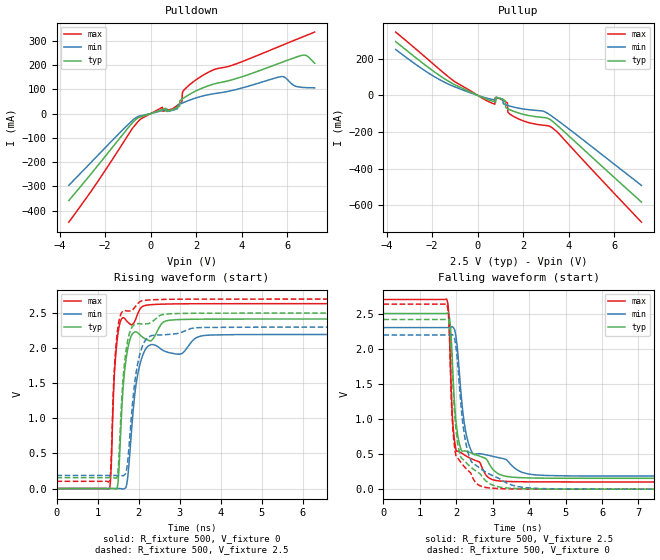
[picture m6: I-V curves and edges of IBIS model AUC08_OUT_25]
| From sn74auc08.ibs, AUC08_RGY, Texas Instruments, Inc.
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[Model]   AUC08_OUT_25
Model_type  Output
Vref =   0
Rref =   500
Cref =   30p
Vmeas =   1.25
| variable   typ   min   max
C_comp   7.45pF   0.27pF   23.62pF
| C_pullup   8.36pF   0.27pF   23.62pF
| C_pulldown   6.53pF   1.89pF   15.75pF
[Temperature Range]   40   100   -40
| Ambient temperature   25   85   -40
[Voltage range]   2.5   2.3   2.7
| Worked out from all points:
|   slope of the pulldown table from 0 to 0.375 V, typ, clamps not added: 30.9 ohm
|   slope of the pullup table from 0 to 0.375 V, typ, clamps not added: 19.2 ohm
|   rising waveform, R_fixture 500, V_fixture 0: 20-80 % time 179ps typ, 248ps min, 131ps max; typ from 0 V to 2.42 V
|   falling waveform, R_fixture 500, V_fixture 2.5: 20-80 % time 223ps typ, 311ps min, 152ps max; typ from 2.5 V to 0.154 V
|   rising waveform, R_fixture 500, V_fixture 2.5: 20-80 % time 177ps typ, 247ps min, 129ps max; typ from 0.154 V to 2.5 V
|   falling waveform, R_fixture 500, V_fixture 0: 20-80 % time 237ps typ, 332ps min, 156ps max; typ from 2.42 V to 0 V
[Pulldown]
| AUC08_OUT_25
|   Voltage   I(typ)   I(min)   I(max)
-3.6V     -357.9mA   -295mA     -446.9mA
-445mV    -13.39mA   -9.086mA   -23.04mA
515mV     17.02mA    12.57mA    25.99mA
1.03V     19.04mA    15.49mA    23.85mA
1.27V     29.99mA    38.36mA    41.3mA
1.37V     59.29mA    42.41mA    48.87mA
1.395V    60.81mA    43.42mA    85.06mA
1.48V     65.92mA    46.77mA    98.72mA
2.545V    114.8mA    77.91mA    170.6mA
5.695V    208.4mA    151.5mA    277.8mA
6.74V     240.4mA    107.1mA    317.8mA
7.2V      207mA      105.9mA    335.2mA
[Pullup]
| AUC08_OUT_25
|   Voltage   I(typ)   I(min)   I(max)
-3.6V     293.6mA    250.5mA    345.5mA
-960mV    55.5mA     44.14mA    71.53mA
730mV     -33.82mA   -24.42mA   -47.21mA
760mV     -34.84mA   -25.13mA   -47.16mA
770mV     -35.18mA   -25.36mA   -13.07mA
1.115V    -23.84mA   -20.26mA   -27.67mA
1.215V    -28.81mA   -50.48mA   -34.67mA
1.295V    -71.05mA   -53.78mA   -40.2mA
1.345V    -74.3mA    -55.73mA   -93.3mA
1.755V    -94.43mA   -68.81mA   -126mA
3.31V     -143.6mA   -118mA     -180.4mA
7.2V      -582.7mA   -491.8mA   -692.5mA
[Ramp]
| AUC08_OUT_25
| variable   typ   min   max
dV/dt_r   1.45/1.80E-10   1.32/2.49E-10   1.59/1.31E-10
dV/dt_f   1.41/2.24E-10   1.28/3.12E-10   1.56/1.54E-10
R_load = 500
[Rising Waveform]
| AUC08_OUT_25
R_fixture =   500
C_fixture =   0
L_fixture =   0
V_fixture =   0
V_fixture_min = 0
V_fixture_max = 0
|   Time   V(typ)   V(min)   V(max)
0s        9.791nV    28.67nV    1.858nV
1.29ns    167.6uV    -2.987uV   3.738mV
1.33ns    302.2uV    -4.433uV   270.1mV
1.415ns   -2.952mV   59.06uV    1.67V
1.525ns   312.5mV    671.3uV    2.307V
1.625ns   1.452V     -6.602mV   2.435V
1.745ns   2.018V     210mV      2.368V
1.935ns   2.232V     1.466V     2.422V
2.16ns    2.133V     1.976V     2.609V
20ns      2.416V     2.195V     2.634V
[Falling Waveform]
| AUC08_OUT_25
R_fixture =   500
C_fixture =   0
L_fixture =   0
V_fixture =   2.5
V_fixture_min = 2.3
V_fixture_max = 2.7
|   Time   V(typ)   V(min)   V(max)
0s        2.5V       2.3V       2.7V
1.74ns    2.503V     2.3V       2.703V
1.79ns    2.5V       2.3V       2.519V
1.835ns   2.34V      2.303V     1.887V
1.9ns     1.735V     2.31V      988.4mV
1.995ns   950.7mV    2.158V     555mV
2.19ns    542.8mV    1.055V     498.2mV
2.35ns    526.9mV    627.2mV    449.4mV
3.035ns   265mV      463.1mV    128.6mV
20ns      154.5mV    186.3mV    102.7mV
[Rising Waveform]
| AUC08_OUT_25
R_fixture =   500
C_fixture =   0
L_fixture =   0
V_fixture =   2.5
V_fixture_min = 2.3
V_fixture_max = 2.7
|   Time   V(typ)   V(min)   V(max)
0s        154.5mV    186.3mV    102.6mV
1.29ns    154.6mV    186.2mV    107.2mV
1.41ns    152.7mV    186.3mV    1.711V
1.515ns   392.1mV    186.8mV    2.365V
1.615ns   1.506V     181.5mV    2.527V
1.72ns    2.057V     309.4mV    2.53V
1.905ns   2.34V      1.502V     2.58V
2.08ns    2.346V     2.008V     2.675V
3.56ns    2.498V     2.295V     2.7V
20ns      2.5V       2.3V       2.7V
[Falling Waveform]
| AUC08_OUT_25
R_fixture =   500
C_fixture =   0
L_fixture =   0
V_fixture =   0
V_fixture_min = 0
V_fixture_max = 0
|   Time   V(typ)   V(min)   V(max)
0s        2.416V     2.195V     2.634V
1.74ns    2.416V     2.195V     2.635V
1.79ns    2.407V     2.195V     2.439V
1.83ns    2.261V     2.196V     1.869V
1.89ns    1.711V     2.201V     992.4mV
1.985ns   887.7mV    2.049V     489.6mV
2.29ns    367.3mV    589.7mV    282.3mV
2.755ns   148.8mV    261.5mV    30.32mV
4.4ns     1.984mV    7.727mV    589.5uV
20ns      23.87uV    3.666uV    11.61uV
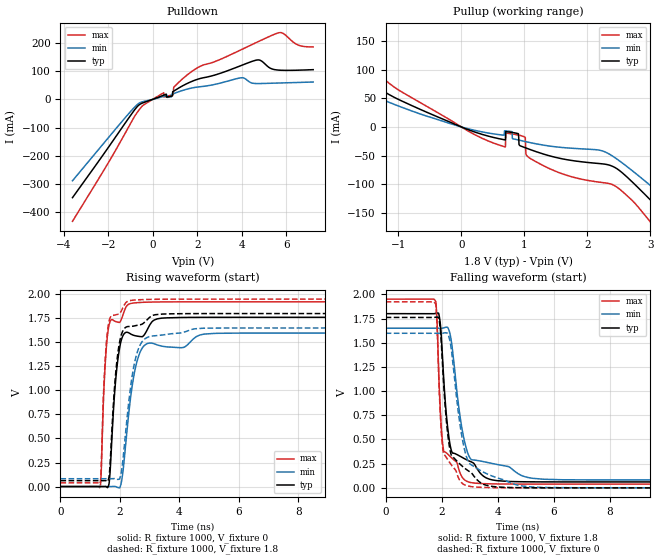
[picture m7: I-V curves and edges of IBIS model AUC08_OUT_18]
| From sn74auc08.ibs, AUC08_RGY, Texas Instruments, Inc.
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[Model]   AUC08_OUT_18
Model_type  Output
Vref =   0
Rref =   1000
Cref =   30p
Vmeas =   0.9
| variable   typ   min   max
C_comp   6.69pF   0.25pF   21.38pF
| C_pullup   7.14pF   1.04pF   21.38pF
| C_pulldown   6.24pF   0.25pF   15.43pF
[Temperature Range]   40   100   -40
| Ambient temperature   25   85   -40
[Voltage range]   1.8   1.65   1.95
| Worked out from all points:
|   slope of the pulldown table from 0 to 0.27 V, typ, clamps not added: 34.4 ohm
|   slope of the pullup table from 0 to 0.27 V, typ, clamps not added: 24.7 ohm
|   rising waveform, R_fixture 1000, V_fixture 0: 20-80 % time 267ps typ, 398ps min, 176ps max; typ from 0 V to 1.76 V
|   falling waveform, R_fixture 1000, V_fixture 1.8: 20-80 % time 316ps typ, 471ps min, 196ps max; typ from 1.8 V to 0.061 V
|   rising waveform, R_fixture 1000, V_fixture 1.8: 20-80 % time 261ps typ, 389ps min, 173ps max; typ from 0.061 V to 1.8 V
|   falling waveform, R_fixture 1000, V_fixture 0: 20-80 % time 325ps typ, 483ps min, 196ps max; typ from 1.76 V to 0 V
[Pulldown]
| AUC08_OUT_18
|   Voltage   I(typ)   I(min)   I(max)
-3.6V     -347.6mA   -287.8mA   -431.2mA
-830mV    -38.94mA   -28.94mA   -62.22mA
-405mV    -11.33mA   -7.446mA   -19.55mA
495mV     14.95mA    10.62mA    23.51mA
885mV     12.26mA    19.06mA    15.87mA
925mV     28.54mA    20.16mA    16.88mA
960mV     30.1mA     21.15mA    44.31mA
2.045V    71.87mA    43.99mA    113.3mA
3.92V     118.2mA    75.85mA    173.7mA
4.625V    138.4mA    55.98mA    200.1mA
5.58V     103.9mA    57.6mA     233.8mA
7.2V      105mA      61.31mA    185.3mA
[Pullup]
| AUC08_OUT_18
|   Voltage   I(typ)   I(min)   I(max)
-3.6V     267.6mA    221.5mA    318.7mA
-2.61V    174.3mA    138.3mA    219.8mA
-2.13V    131.5mA    101.8mA    171.7mA
110mV     -4.812mA   -3.244mA   -7.318mA
695mV     -22.64mA   -6.826mA   -34.84mA
705mV     -8.168mA   -6.941mA   -10.57mA
980mV     -34.9mA    -24.66mA   -16.5mA
1.11V     -40.21mA   -27.81mA   -56.13mA
2.25V     -64.62mA   -42.31mA   -97.29mA
3.1V      -138.6mA   -111.4mA   -179.7mA
3.915V    -230.4mA   -188mA     -289.7mA
7.2V      -598mA     -503.3mA   -721.1mA
[Ramp]
| AUC08_OUT_18
| variable   typ   min   max
dV/dt_r   1.06/2.67E-10   0.97/4.00E-10   1.16/1.76E-10
dV/dt_f   1.05/3.17E-10   0.95/4.75E-10   1.15/1.97E-10
R_load = 1000
[Rising Waveform]
| AUC08_OUT_18
R_fixture =   1000
C_fixture =   0
L_fixture =   0
V_fixture =   0
V_fixture_min = 0
V_fixture_max = 0
|   Time   V(typ)   V(min)   V(max)
0s        7.669nV    26.14nV    1.117nV
1.33ns    -4.227uV   -2.974uV   -4.822mV
1.485ns   449.1uV    -11.66uV   1.155V
1.605ns   -1.293mV   -5.677uV   1.627V
1.955ns   1.374V     -11.6mV    1.708V
2.09ns    1.561V     123.7mV    1.774V
2.345ns   1.591V     885.8mV    1.903V
2.83ns    1.582V     1.47V      1.917V
4.835ns   1.761V     1.587V     1.922V
20ns      1.761V     1.597V     1.922V
[Falling Waveform]
| AUC08_OUT_18
R_fixture =   1000
C_fixture =   0
L_fixture =   0
V_fixture =   1.8
V_fixture_min = 1.65
V_fixture_max = 1.95
|   Time   V(typ)   V(min)   V(max)
0s        1.8V       1.65V      1.95V
1.79ns    1.803V     1.65V      1.926V
1.94ns    1.72V      1.649V     861.6mV
2.065ns   1.161V     1.653V     389.6mV
2.195ns   670.9mV    1.66V      353.9mV
2.345ns   385.9mV    1.512V     312.6mV
2.675ns   323.6mV    699.3mV    140.1mV
2.96ns    280.2mV    336.5mV    60.91mV
5.635ns   61.7mV     89.17mV    38.82mV
20ns      61.08mV    81.21mV    38.69mV
[Rising Waveform]
| AUC08_OUT_18
R_fixture =   1000
C_fixture =   0
L_fixture =   0
V_fixture =   1.8
V_fixture_min = 1.65
V_fixture_max = 1.95
|   Time   V(typ)   V(min)   V(max)
0s        61.05mV    81.2mV     38.68mV
1.33ns    61.04mV    81.2mV     35.1mV
1.485ns   61.49mV    81.19mV    1.2V
1.6ns     60mV       81.2mV     1.658V
1.94ns    1.406V     74.56mV    1.792V
2.07ns    1.598V     194.1mV    1.84V
2.305ns   1.665V     896mV      1.932V
2.785ns   1.697V     1.521V     1.945V
4.515ns   1.799V     1.641V     1.95V
20ns      1.8V       1.65V      1.95V
[Falling Waveform]
| AUC08_OUT_18
R_fixture =   1000
C_fixture =   0
L_fixture =   0
V_fixture =   0
V_fixture_min = 0
V_fixture_max = 0
|   Time   V(typ)   V(min)   V(max)
0s        1.761V     1.597V     1.922V
1.79ns    1.764V     1.597V     1.895V
1.93ns    1.69V      1.597V     884mV
2.055ns   1.141V     1.599V     370.3mV
2.185ns   637.9mV    1.601V     305.2mV
2.32ns    360.9mV    1.477V     247.2mV
2.635ns   250.2mV    688.9mV    82.21mV
2.875ns   191.1mV    329.2mV    24.05mV
5.195ns   996.1uV    9.726mV    211.6uV
20ns      28.23uV    5.954uV    12.23uV
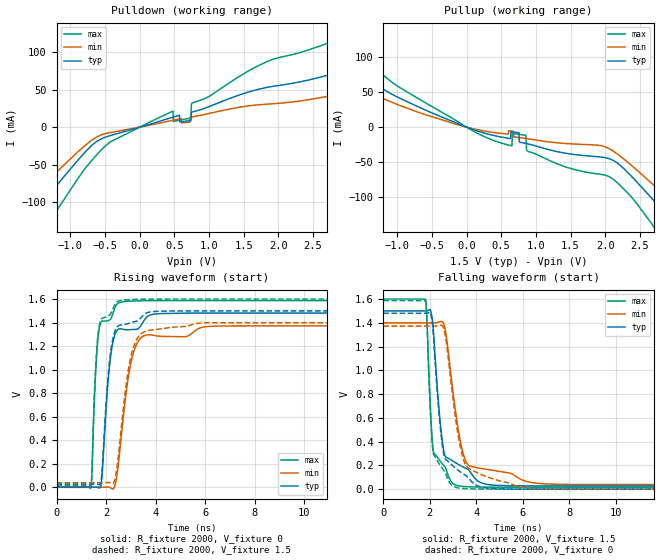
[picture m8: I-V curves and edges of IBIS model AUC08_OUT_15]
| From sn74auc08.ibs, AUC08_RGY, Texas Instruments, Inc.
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[Model]   AUC08_OUT_15
Model_type  Output
Vref =   0
Rref =   2000
Cref =   15p
Vmeas =   0.75
| variable   typ   min   max
C_comp   6.42pF   1.69pF   19.05pF
| C_pullup   6.13pF   1.69pF   19.05pF
| C_pulldown   6.70pF   3.60pF   15.20pF
[Temperature Range]   40   100   -40
| Ambient temperature   25   85   -40
[Voltage range]   1.5   1.4   1.6
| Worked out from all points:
|   slope of the pulldown table from 0 to 0.225 V, typ, clamps not added: 36.6 ohm
|   slope of the pullup table from 0 to 0.225 V, typ, clamps not added: 29.5 ohm
|   rising waveform, R_fixture 2000, V_fixture 0: 20-80 % time 339ps typ, 511ps min, 215ps max; typ from 0 V to 1.48 V
|   falling waveform, R_fixture 2000, V_fixture 1.5: 20-80 % time 404ps typ, 607ps min, 237ps max; typ from 1.5 V to 0.027 V
|   rising waveform, R_fixture 2000, V_fixture 1.5: 20-80 % time 333ps typ, 501ps min, 211ps max; typ from 0.027 V to 1.5 V
|   falling waveform, R_fixture 2000, V_fixture 0: 20-80 % time 404ps typ, 615ps min, 235ps max; typ from 1.48 V to 0 V
[Pulldown]
| AUC08_OUT_15
|   Voltage   I(typ)   I(min)   I(max)
-3.6V     -343mA     -284.8mA   -423.7mA
-2.105V   -179.1mA   -144.1mA   -232.4mA
-1.795V   -144.7mA   -115.1mA   -192.1mA
-1.395V   -99.88mA   -78mA      -138.7mA
-395mV    -10.45mA   -6.753mA   -18.28mA
480mV     13.33mA    9.224mA    21.44mA
485mV     13.46mA    9.315mA    7.619mA
735mV     8.724mA    13.39mA    12.06mA
755mV     20.22mA    13.69mA    32.02mA
1.69V     50.03mA    29.61mA    81.13mA
3.34V     86.07mA    49.98mA    134.3mA
7.2V      80.6mA     45.5mA     141.2mA
[Pullup]
| AUC08_OUT_15
|   Voltage   I(typ)   I(min)   I(max)
-3.6V     254.2mA    195.1mA    304.8mA
-2.875V   187.5mA    148mA      233.8mA
-2.45V    149.7mA    116.2mA    192.1mA
-1.91V    104.4mA    79.22mA    139.6mA
100mV     -3.652mA   -2.395mA   -5.808mA
650mV     -6.722mA   -5.654mA   -26.6mA
855mV     -23.22mA   -16.17mA   -11.7mA
885mV     -23.88mA   -16.62mA   -34.51mA
2.105V    -46.97mA   -33.55mA   -73.62mA
2.76V     -111.3mA   -88.18mA   -150.1mA
3.36V     -178.2mA   -143.6mA   -230.9mA
7.2V      -605.9mA   -510.3mA   -734mA
[Ramp]
| AUC08_OUT_15
| variable   typ   min   max
dV/dt_r   0.89/3.39E-10   0.83/5.13E-10   0.96/2.15E-10
dV/dt_f   0.89/4.09E-10   0.82/6.16E-10   0.95/2.40E-10
R_load = 2000
[Rising Waveform]
| AUC08_OUT_15
R_fixture =   2000
C_fixture =   0
L_fixture =   0
V_fixture =   0
V_fixture_min = 0
V_fixture_max = 0
|   Time   V(typ)   V(min)   V(max)
0s        7.042nV    26.32nV    876.9pV
1.39ns    -6.911uV   -1.597uV   -1.383mV
1.6ns     651.7uV    -9.568uV   1.057V
1.79ns    9.352mV    -20.89uV   1.402V
2.16ns    1.067V     -2.622mV   1.425V
2.355ns   1.296V     11.92mV    1.524V
2.525ns   1.346V     248.3mV    1.568V
3.005ns   1.34V      1.059V     1.583V
3.59ns    1.434V     1.293V     1.586V
20ns      1.481V     1.373V     1.587V
[Falling Waveform]
| AUC08_OUT_15
R_fixture =   2000
C_fixture =   0
L_fixture =   0
V_fixture =   1.5
V_fixture_min = 1.4
V_fixture_max = 1.6
|   Time   V(typ)   V(min)   V(max)
0s        1.5V       1.4V       1.6V
1.82ns    1.5V       1.4V       1.596V
2.035ns   1.502V     1.4V       632.5mV
2.15ns    1.339V     1.399V     318.9mV
2.395ns   671.1mV    1.407V     249.7mV
2.585ns   338.3mV    1.396V     201.7mV
3.11ns    222.5mV    649.6mV    34.96mV
3.65ns    166.8mV    202.9mV    20.61mV
6.335ns   27.7mV     56.75mV    16.5mV
20ns      27.21mV    38.79mV    16.41mV
[Rising Waveform]
| AUC08_OUT_15
R_fixture =   2000
C_fixture =   0
L_fixture =   0
V_fixture =   1.5
V_fixture_min = 1.4
V_fixture_max = 1.6
|   Time   V(typ)   V(min)   V(max)
0s        27.17mV    38.78mV    16.4mV
1.39ns    27.17mV    38.78mV    16.34mV
1.6ns     27.8mV     38.77mV    1.084V
1.79ns    43.7mV     38.76mV    1.423V
2.15ns    1.087V     37.43mV    1.465V
2.335ns   1.311V     51.63mV    1.544V
2.495ns   1.371V     258.2mV    1.583V
3ns       1.399V     1.107V     1.596V
3.635ns   1.482V     1.329V     1.599V
20ns      1.5V       1.4V       1.6V
[Falling Waveform]
| AUC08_OUT_15
R_fixture =   2000
C_fixture =   0
L_fixture =   0
V_fixture =   0
V_fixture_min = 0
V_fixture_max = 0
|   Time   V(typ)   V(min)   V(max)
0s        1.481V     1.373V     1.587V
1.82ns    1.48V      1.373V     1.581V
2.035ns   1.479V     1.372V     605.8mV
2.15ns    1.306V     1.372V     298.9mV
2.38ns    667.2mV    1.378V     220.7mV
2.565ns   329.8mV    1.367V     165.6mV
3.055ns   185.5mV    672.5mV    19.84mV
3.59ns    108.6mV    188.4mV    4.422mV
5.91ns    726.5uV    18.68mV    127.3uV
20ns      33.67uV    8.508uV    13.33uV
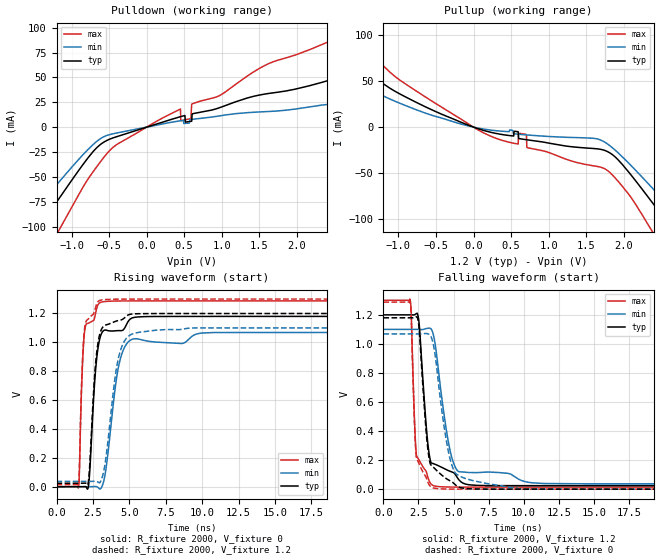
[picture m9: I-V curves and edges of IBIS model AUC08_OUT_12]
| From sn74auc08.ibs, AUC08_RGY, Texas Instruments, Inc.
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[Model]   AUC08_OUT_12
Model_type  Output
Vref =   0
Rref =   2000
Cref =   15p
Vmeas =   0.6
| variable   typ   min   max
C_comp   5.93pF   2.37pF   15.74pF
| C_pullup   5.52pF   2.37pF   15.74pF
| C_pulldown   6.35pF   4.16pF   14.94pF
[Temperature Range]   40   100   -40
| Ambient temperature   25   85   -40
[Voltage range]   1.2   1.1   1.3
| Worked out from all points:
|   slope of the pulldown table from 0 to 0.18 V, typ, clamps not added: 42.3 ohm
|   slope of the pullup table from 0 to 0.18 V, typ, clamps not added: 38.7 ohm
|   rising waveform, R_fixture 2000, V_fixture 0: 20-80 % time 473ps typ, 799ps min, 276ps max; typ from 0 V to 1.18 V
|   falling waveform, R_fixture 2000, V_fixture 1.2: 20-80 % time 563ps typ, 952ps min, 287ps max; typ from 1.2 V to 0.024 V
|   rising waveform, R_fixture 2000, V_fixture 1.2: 20-80 % time 462ps typ, 789ps min, 271ps max; typ from 0.024 V to 1.2 V
|   falling waveform, R_fixture 2000, V_fixture 0: 20-80 % time 561ps typ, 958ps min, 283ps max; typ from 1.18 V to 0 V
[Pulldown]
| AUC08_OUT_12
|   Voltage   I(typ)   I(min)   I(max)
-3.6V     -338.3mA   -281.2mA   -417.3mA
-1.81V    -142.4mA   -113.5mA   -188.2mA
-1.485V   -106.7mA   -83.68mA   -145.8mA
-1.225V   -78.14mA   -60.24mA   -111.4mA
-715mV    -24.74mA   -17.64mA   -45.05mA
-390mV    -9.376mA   -5.759mA   -17.06mA
450mV     10.5mA     6.398mA    18.24mA
590mV     5.848mA    7.731mA    8.546mA
605mV     12.96mA    7.861mA    23.36mA
2.86V     55.94mA    19.09mA    100.7mA
3.425V    44.57mA    20.08mA    119.3mA
7.2V      57.06mA    26.82mA    108mA
[Pullup]
| AUC08_OUT_12
|   Voltage   I(typ)   I(min)   I(max)
-3.6V     224.6mA    100.8mA    291.5mA
-2.7V     158.6mA    66.17mA    205.2mA
-2.11V    110.3mA    77.88mA    148.7mA
-1.68V    77.88mA    55.75mA    108.7mA
-1.025V   38.18mA    27.56mA    53.97mA
50mV      -1.427mA   -842.9uA   -2.489mA
700mV     -13.68mA   -8.451mA   -7.891mA
1.78V     -26.5mA    -18.1mA    -47.09mA
2.4V      -84.34mA   -68.12mA   -116.4mA
2.695V    -116.7mA   -94.74mA   -156.1mA
3.045V    -155.5mA   -127mA     -202.8mA
7.2V      -615.6mA   -521.5mA   -745mA
[Ramp]
| AUC08_OUT_12
| variable   typ   min   max
dV/dt_r   0.72/4.77E-10   0.65/8.09E-10   0.78/2.78E-10
dV/dt_f   0.71/5.66E-10   0.64/9.58E-10   0.78/2.91E-10
R_load = 2000
[Rising Waveform]
| AUC08_OUT_12
R_fixture =   2000
C_fixture =   0
L_fixture =   0
V_fixture =   0
V_fixture_min = 0
V_fixture_max = 0
|   Time   V(typ)   V(min)   V(max)
0s        6.587nV    27.93nV    705.3pV
1.51ns    -3.877uV   -913.9nV   -2.264mV
1.845ns   260uV      -3.796uV   972.3mV
2.175ns   -8.109mV   -43.97uV   1.133V
2.67ns    794.6mV    1.443mV    1.196V
3.03ns    1.047V     -13.51mV   1.277V
3.39ns    1.085V     120.6mV    1.283V
4.285ns   1.081V     845.3mV    1.287V
5.205ns   1.17V      1.022V     1.287V
34.99ns   1.18V      1.069V     1.287V
[Falling Waveform]
| AUC08_OUT_12
R_fixture =   2000
C_fixture =   0
L_fixture =   0
V_fixture =   1.2
V_fixture_min = 1.1
V_fixture_max = 1.3
|   Time   V(typ)   V(min)   V(max)
0s        1.2V       1.1V       1.3V
1.905ns   1.2V       1.1V       1.303V
1.985ns   1.2V       1.1V       1.203V
2.265ns   1.203V     1.1V       364.4mV
2.435ns   1.205V     1.1V       217.4mV
3.165ns   315.9mV    1.107V     83.62mV
3.585ns   174.8mV    1.053V     23.67mV
4.65ns    127.1mV    315.1mV    14.79mV
5.38ns    64.65mV    120.3mV    14.17mV
34.99ns   24mV       36.64mV    13.87mV
[Rising Waveform]
| AUC08_OUT_12
R_fixture =   2000
C_fixture =   0
L_fixture =   0
V_fixture =   1.2
V_fixture_min = 1.1
V_fixture_max = 1.3
|   Time   V(typ)   V(min)   V(max)
0s        23.98mV    36.64mV    13.86mV
1.505ns   23.97mV    36.64mV    10.78mV
1.835ns   24.17mV    36.64mV    980.1mV
2.165ns   22.55mV    36.61mV    1.161V
2.65ns    814.1mV    37.82mV    1.23V
2.98ns    1.061V     28.64mV    1.291V
3.345ns   1.119V     167.5mV    1.296V
4.24ns    1.151V     886.9mV    1.299V
5.285ns   1.197V     1.062V     1.3V
34.99ns   1.2V       1.1V       1.3V
[Falling Waveform]
| AUC08_OUT_12
R_fixture =   2000
C_fixture =   0
L_fixture =   0
V_fixture =   0
V_fixture_min = 0
V_fixture_max = 0
|   Time   V(typ)   V(min)   V(max)
0s        1.18V      1.069V     1.287V
1.9ns     1.18V      1.069V     1.291V
1.98ns    1.18V      1.069V     1.194V
2.26ns    1.182V     1.069V     347.2mV
2.425ns   1.181V     1.069V     200.9mV
3.135ns   304.2mV    1.07V      56.68mV
3.51ns    156mV      1.017V     10.08mV
4.725ns   58.85mV    218.1mV    719uV
5.89ns    4.247mV    71.58mV    165uV
34.99ns   18.79uV    42.65nV    7.939uV
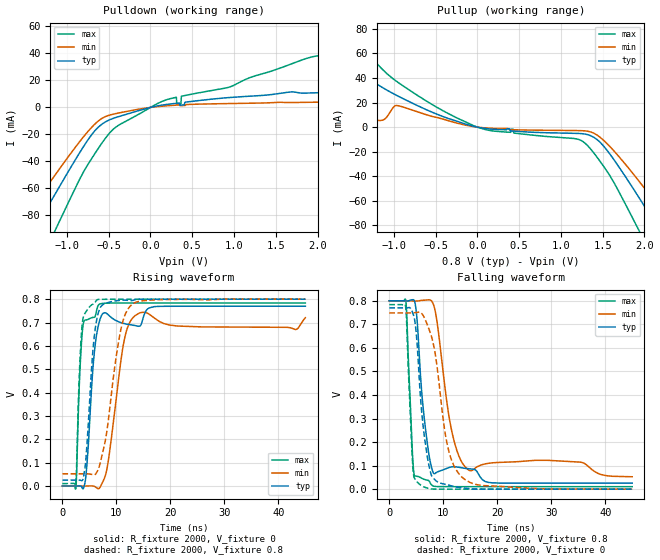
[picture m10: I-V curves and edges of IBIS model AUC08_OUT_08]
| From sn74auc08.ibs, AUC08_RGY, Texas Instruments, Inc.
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[Model]   AUC08_OUT_08
Model_type  Output
Vref =   0
Rref =   2000
Cref =   15p
Vmeas =   0.4
| variable   typ   min   max
C_comp   5.67pF   2.72pF   7.64pF
| C_pullup   5.14pF   2.72pF   7.64pF
| C_pulldown   6.20pF   5.44pF   6.81pF
[Temperature Range]   40   100   -40
| Ambient temperature   25   85   -40
[Voltage range]   0.8   0.8   0.8
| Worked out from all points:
|   slope of the pulldown table from 0 to 0.12 V, typ, clamps not added: 77.1 ohm
|   slope of the pullup table from 0 to 0.12 V, typ, clamps not added: 92.8 ohm
|   rising waveform, R_fixture 2000, V_fixture 0: 20-80 % time 1.4ns typ, 2.36ns min, 817ps max; typ from 0 V to 0.77 V
|   falling waveform, R_fixture 2000, V_fixture 0.8: 20-80 % time 1.77ns typ, 2.85ns min, 869ps max; typ from 0.8 V to 0.026 V
|   rising waveform, R_fixture 2000, V_fixture 0.8: 20-80 % time 1.37ns typ, 2.66ns min, 763ps max; typ from 0.025 V to 0.8 V
|   falling waveform, R_fixture 2000, V_fixture 0: 20-80 % time 1.78ns typ, 2.86ns min, 867ps max; typ from 0.77 V to 0 V
[Pulldown]
| AUC08_OUT_08
|   Voltage   I(typ)   I(min)   I(max)
-3.6V     -332mA     -277.5mA   -406.5mA
-1.635V   -117.5mA   -94.15mA   -155.2mA
-1.375V   -89.26mA   -70.66mA   -121.5mA
-1.155V   -65.6mA    -51.21mA   -92.88mA
-630mV    -14.96mA   -10.34mA   -30.86mA
-430mV    -7.788mA   -4.786mA   -15.33mA
-90mV     -1.494mA   -794.3uA   -3.292mA
210mV     2.329mA    1.254mA    6.027mA
365mV     1.692mA    1.285mA    2.781mA
1.98V     10.83mA    3.867mA    38.03mA
2.365V    11.74mA    4.199mA    33.49mA
7.2V      23.85mA    8.894mA    59.33mA
[Pullup]
| AUC08_OUT_08
|   Voltage   I(typ)   I(min)   I(max)
-3.6V     79.74mA    9.11mA     185.5mA
-3.08V    78.24mA    9.441mA    162.7mA
-1.59V    27.55mA    11.02mA    82.8mA
-1.305V   38.33mA    6.645mA    59.6mA
-1.13V    31.97mA    5.759mA    46.58mA
-975mV    26.17mA    17.62mA    37.64mA
-245mV    4.854mA    3.296mA    7.479mA
1.36V     -7.061mA   -3.966mA   -18.08mA
1.875V    -50.9mA    -38.75mA   -76.11mA
2.115V    -76.5mA    -59.54mA   -107.8mA
2.405V    -108mA     -85.49mA   -146mA
7.2V      -633.7mA   -537.1mA   -765.1mA
[Ramp]
| AUC08_OUT_08
| variable   typ   min   max
dV/dt_r   0.47/1.41E-09   0.45/2.50E-09   0.48/8.21E-10
dV/dt_f   0.47/1.77E-09   0.45/2.85E-09   0.48/8.75E-10
R_load = 2000
[Rising Waveform]
| AUC08_OUT_08
R_fixture =   2000
C_fixture =   0
L_fixture =   0
V_fixture =   0
V_fixture_min = 0
V_fixture_max = 0
|   Time   V(typ)   V(min)   V(max)
0s        8.079nV    45.62nV    527.9pV
2.505ns   -48.71uV   -7.01uV    -8.173mV
3.33ns    546uV      -24.37uV   535mV
4.155ns   11.64mV    39.79uV    710.4mV
5.78ns    539.8mV    -260.6uV   722.3mV
6.795ns   700.3mV    -10.8mV    777.8mV
8.38ns    735.8mV    90.37mV    783.3mV
11.48ns   695.6mV    628.1mV    783.6mV
13.44ns   687.1mV    729.5mV    783.7mV
45ns      770mV      720.9mV    783.8mV
[Falling Waveform]
| AUC08_OUT_08
R_fixture =   2000
C_fixture =   0
L_fixture =   0
V_fixture =   0.8
V_fixture_min = 0.8
V_fixture_max = 0.8
|   Time   V(typ)   V(min)   V(max)
0s        800mV      800mV      800mV
3.055ns   799.7mV    800mV      802.1mV
4.28ns    804.6mV    799.6mV    155.9mV
4.695ns   797.3mV    799.2mV    55.29mV
6.475ns   301.4mV    802.8mV    41.46mV
8.26ns    65.8mV     778.9mV    12.55mV
11.48ns   94.51mV    255.9mV    10.67mV
14.47ns   87.3mV     85.31mV    10.64mV
29.29ns   25.56mV    122.6mV    10.61mV
45ns      25.5mV     52.66mV    10.6mV
[Rising Waveform]
| AUC08_OUT_08
R_fixture =   2000
C_fixture =   0
L_fixture =   0
V_fixture =   0.8
V_fixture_min = 0.8
V_fixture_max = 0.8
|   Time   V(typ)   V(min)   V(max)
0s        25.46mV    52.25mV    10.6mV
2.49ns    25.44mV    52.25mV    11.02mV
3.215ns   25.49mV    52.3mV     523mV
3.88ns    34.59mV    52.37mV    724.2mV
5.65ns    581.1mV    48.98mV    778.5mV
6.37ns    714.1mV    59.26mV    796.7mV
8.07ns    783.3mV    210.5mV    799.7mV
10.81ns   795.3mV    669.2mV    799.9mV
12.85ns   794.3mV    776.7mV    799.9mV
45ns      800mV      800mV      800mV
[Falling Waveform]
| AUC08_OUT_08
R_fixture =   2000
C_fixture =   0
L_fixture =   0
V_fixture =   0
V_fixture_min = 0
V_fixture_max = 0
|   Time   V(typ)   V(min)   V(max)
0s        770mV      748.6mV    783.8mV
3.02ns    769.9mV    748.5mV    774.9mV
4.415ns   744.2mV    748.9mV    79.06mV
5.025ns   653.1mV    750.5mV    33.73mV
5.83ns    374.2mV    749.4mV    17.13mV
6.805ns   173.3mV    711.9mV    6.415mV
7.84ns    57.04mV    646.2mV    616uV
10.77ns   18.7mV     186.3mV    70.57uV
13.48ns   5.708mV    50.33mV    44.27uV
45ns      27.87uV    3.293uV    8.162uV
